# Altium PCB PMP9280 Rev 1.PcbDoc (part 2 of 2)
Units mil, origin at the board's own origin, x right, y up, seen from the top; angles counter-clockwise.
Board outline 4050 x 2360 mil, 4 copper layers (Top Layer, MidLayer1, MidLayer2, Bottom Layer), stack 61.2 mil thick; 80 components, 27 nets, 139 pads, 275 vias.

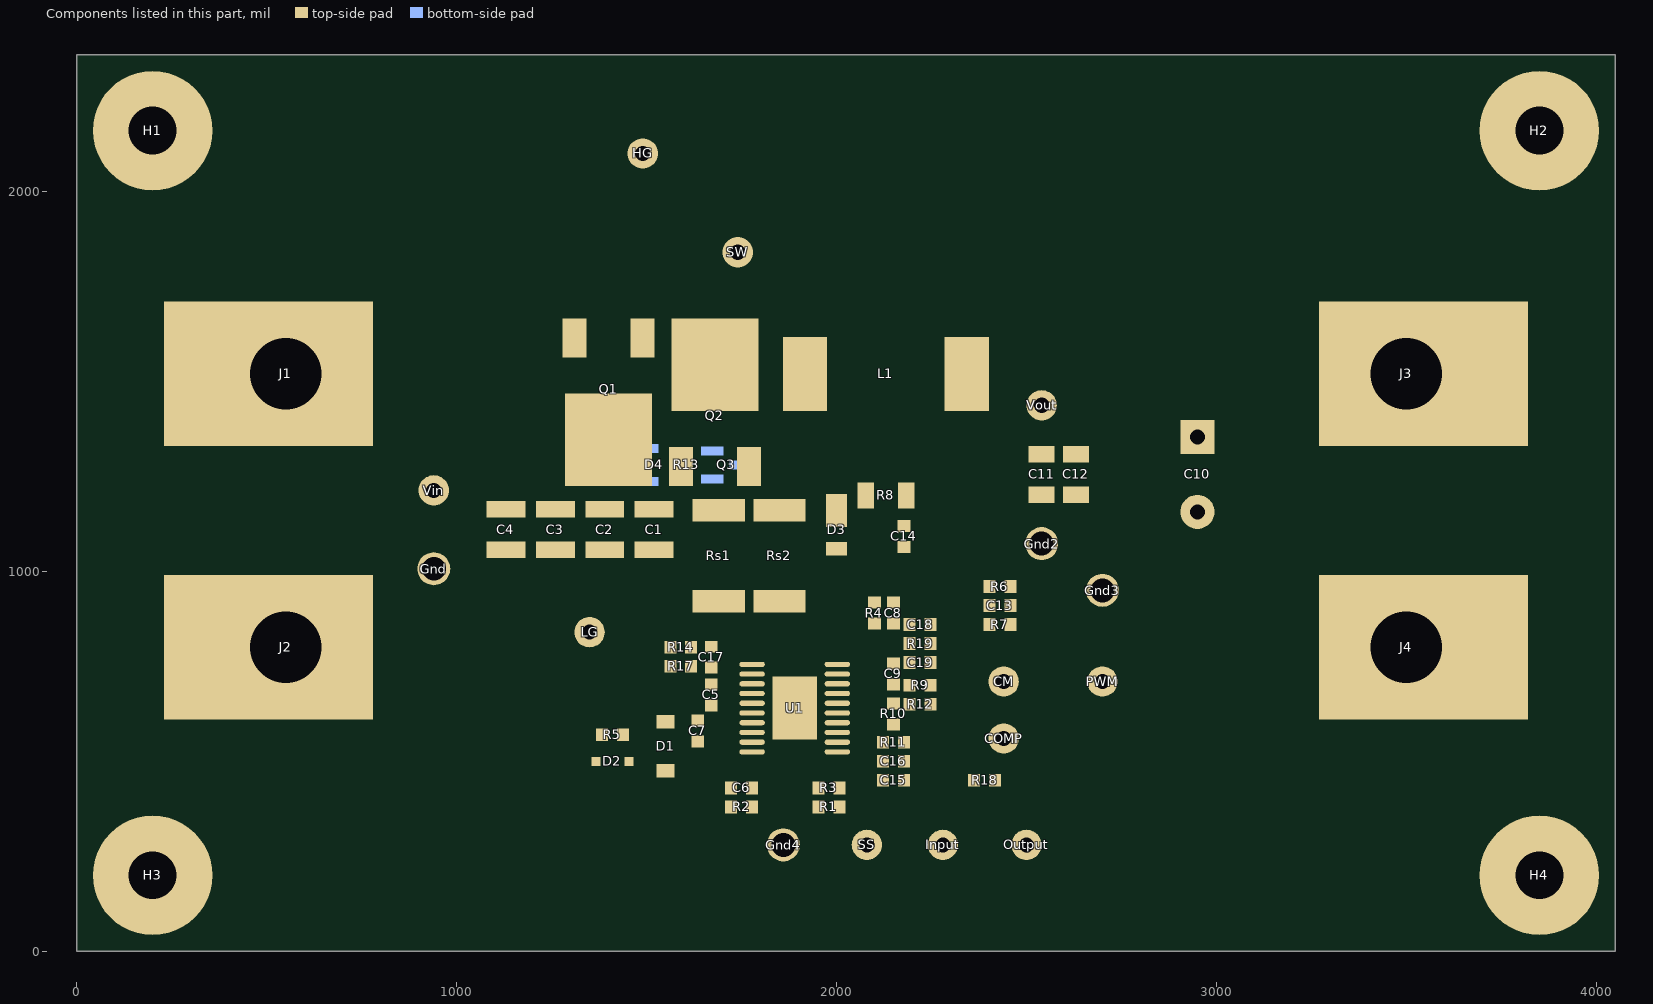
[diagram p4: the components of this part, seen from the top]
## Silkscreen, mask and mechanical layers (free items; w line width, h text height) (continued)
M12 Stackup:
  drawing of 418 lines, arcs and shapes, not listed
  text "Layer" at 5935.74,6990.37 h60
  text "Name" at 6345.65,6990.37 h60
  text "Material" at 7275.4,6990.37 h60
  text "Thickness" at 8135.16,6990.37 h60
  text "Constant" at 8785,6990.37 h60
  text "Board Layer Stack" at 9354.86,6990.37 h60
  text "1" at 5935.74,6870.37 h60
  text "Top Overlay" at 6345.65,6870.37 h60
  text "2" at 5935.74,6750.37 h60
  text "Top Solder" at 6345.65,6750.37 h60
  text "Solder Resist" at 7275.4,6750.37 h60
  text "0.40mil" at 8135.16,6750.37 h60
  text "3.5" at 8785,6750.37 h60
  text "3" at 5935.74,6630.37 h60
  text "Top Layer" at 6345.65,6630.37 h60
  text "Copper" at 7275.4,6630.37 h60
  text "1.40mil" at 8135.16,6630.37 h60
  text "4" at 5935.74,6510.37 h60
  text "Dielectric1" at 6345.65,6510.37 h60
  text "FR-4" at 7275.4,6510.37 h60
  text "12.60mil" at 8135.16,6510.37 h60
  text "4.8" at 8785,6510.37 h60
  text "5" at 5935.74,6390.37 h60
  text "MidLayer1" at 6345.65,6390.37 h60
  text "Copper" at 7275.4,6390.37 h60
  text "1.40mil" at 8135.16,6390.37 h60
  text "6" at 5935.74,6270.37 h60
  text "Dielectric2" at 6345.65,6270.37 h60
  text "FR-4" at 7275.4,6270.37 h60
  text "30.40mil" at 8135.16,6270.37 h60
  text "4.8" at 8785,6270.37 h60
  text "7" at 5935.74,6150.37 h60
  text "MidLayer2" at 6345.65,6150.37 h60
  text "Copper" at 7275.4,6150.37 h60
  text "1.40mil" at 8135.16,6150.37 h60
  text "8" at 5935.74,6030.37 h60
  text "Dielectric3" at 6345.65,6030.37 h60
  text "FR-4" at 7275.4,6030.37 h60
  text "12.60mil" at 8135.16,6030.37 h60
  text "4.8" at 8785,6030.37 h60
  text "9" at 5935.74,5910.37 h60
  text "Bottom Layer" at 6345.65,5910.37 h60
  text "Copper" at 7275.4,5910.37 h60
  text "1.40mil" at 8135.16,5910.37 h60
  text "10" at 5935.74,5790.37 h60
  text "Bottom Solder" at 6345.65,5790.37 h60
  text "Solder Resist" at 7275.4,5790.37 h60
  text "0.40mil" at 8135.16,5790.37 h60
  text "3.5" at 8785,5790.37 h60
  text "11" at 5935.74,5670.37 h60
  text "Bottom Overlay" at 6345.65,5670.37 h60
  text ".Layer_Name" at 17,-1418.49 h60
M13 Component Bodies Top:
  text ".Layer_Name" at 17,-1418.49 h60
M14 Component Bodies Bottom:
  text ".Layer_Name" at 17,-1418.49 h60
M15 Courtyards Top:
  text ".Layer_Name" at 17,-1418.49 h60
M16 Courtyards Bottom:
  text ".Layer_Name" at 17,-1418.49 h60
Drill Drawing:
  circle w10: c4865.8,1978.37 r24.91
  lines w10: 4840.89,1081.62 4865.8,1056.71 4890.71,1081.62 4865.8,1106.53 4840.89,1081.62 ; 4840.89,1206.17 4840.89,1218.62 4853.35,1231.08 4840.89,1243.53 4840.89,1255.99 4853.35,1255.99 4865.8,1243.53 4878.26,1255.99 4890.71,1255.99 4890.71,1243.53 4878.26,1231.08 4890.71,1218.62 4890.71,1206.17 4878.26,1206.17 4865.8,1218.62 4853.35,1206.17 4840.89,1206.17 ; 4840.89,1368.08 4853.35,1368.08 4853.35,1355.63 4878.26,1355.63 4878.26,1368.08 4890.71,1368.08 4890.71,1392.99 4878.26,1392.99 4878.26,1405.45 4853.35,1405.45 4853.35,1392.99 4840.89,1392.99 4840.89,1368.08 ; 4840.89,1505.09 4865.8,1517.54 4890.71,1505.09 4878.26,1530 4890.71,1554.91 4865.8,1542.45 4840.89,1554.91 4853.35,1530 4840.89,1505.09 ; 4840.89,1667 4853.35,1667 4865.8,1654.54 4878.26,1667 4890.71,1667 4878.26,1679.45 4890.71,1691.91 4878.26,1691.91 4865.8,1704.36 4853.35,1691.91 4840.89,1691.91 4853.35,1679.45 4840.89,1667 ; 4840.89,1853.82 4890.71,1853.82 4865.8,1804 4840.89,1853.82 ; 4840.89,2102.92 4890.71,2102.92 4890.71,2152.74 4840.89,2152.74 4840.89,2102.92
  lines w12: 4773,1011.87 6892.4,1011.87 ; 4773,2207.54 6892.4,2207.54 ; 5143.67,862.41 5143.67,2357 ; 5500.78,862.41 5500.78,2357 ; 6162.79,862.41 6162.79,2357 ; 6447.14,862.41 6447.14,2357 ; 4773,862.41 6892.4,862.41 6892.4,2357 4773,2357 4773,862.41
  text "Symbol" at 4862.68,2252.38 h72
  text "Quantity" at 5188.51,2252.38 h72
  text "Finished Hole Size" at 5545.62,2252.38 h72
  text "Plated" at 6207.62,2252.38 h72
  text "Hole Type" at 6491.98,2252.38 h72
  text "100" at 5188.51,2102.92 h60
  text "10.00mil (0.254mm)" at 5545.62,2102.92 h60
  text "PTH" at 6207.62,2102.92 h60
  text "Round" at 6491.98,2102.92 h60
  text "58" at 5188.51,1953.46 h60
  text "12.00mil (0.305mm)" at 5545.62,1953.46 h60
  text "PTH" at 6207.62,1953.46 h60
  text "Round" at 6491.98,1953.46 h60
  text "5" at 5188.51,1804 h60
  text "15.00mil (0.381mm)" at 5545.62,1804 h60
  text "PTH" at 6207.62,1804 h60
  text "Round" at 6491.98,1804 h60
  text "112" at 5188.51,1654.54 h60
  text "16.00mil (0.406mm)" at 5545.62,1654.54 h60
  text "PTH" at 6207.62,1654.54 h60
  text "Round" at 6491.98,1654.54 h60
  text "13" at 5188.51,1505.09 h60
  text "40.00mil (1.016mm)" at 5545.62,1505.09 h60
  text "PTH" at 6207.62,1505.09 h60
  text "Round" at 6491.98,1505.09 h60
  text "4" at 5188.51,1355.63 h60
  text "63.00mil (1.600mm)" at 5545.62,1355.63 h60
  text "PTH" at 6207.62,1355.63 h60
  text "Round" at 6491.98,1355.63 h60
  text "4" at 5188.51,1206.17 h60
  text "125.98mil (3.200mm)" at 5545.62,1206.17 h60
  text "PTH" at 6207.62,1206.17 h60
  text "Round" at 6491.98,1206.17 h60
  text "4" at 5188.51,1056.71 h60
  text "188.00mil (4.775mm)" at 5545.62,1056.71 h60
  text "PTH" at 6207.62,1056.71 h60
  text "Round" at 6491.98,1056.71 h60
  text "300 Total" at 5188.51,907.25 h60
  text ".Layer_Name" at 17,-1418.49 h60

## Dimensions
0,0 to 0,2360 on M2 Board Dimensions
0,0 to 4050,0 on M2 Board Dimensions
